VERSION 5.7 ;
  NOWIREEXTENSIONATPIN ON ;
  DIVIDERCHAR "/" ;
  BUSBITCHARS "[]" ;
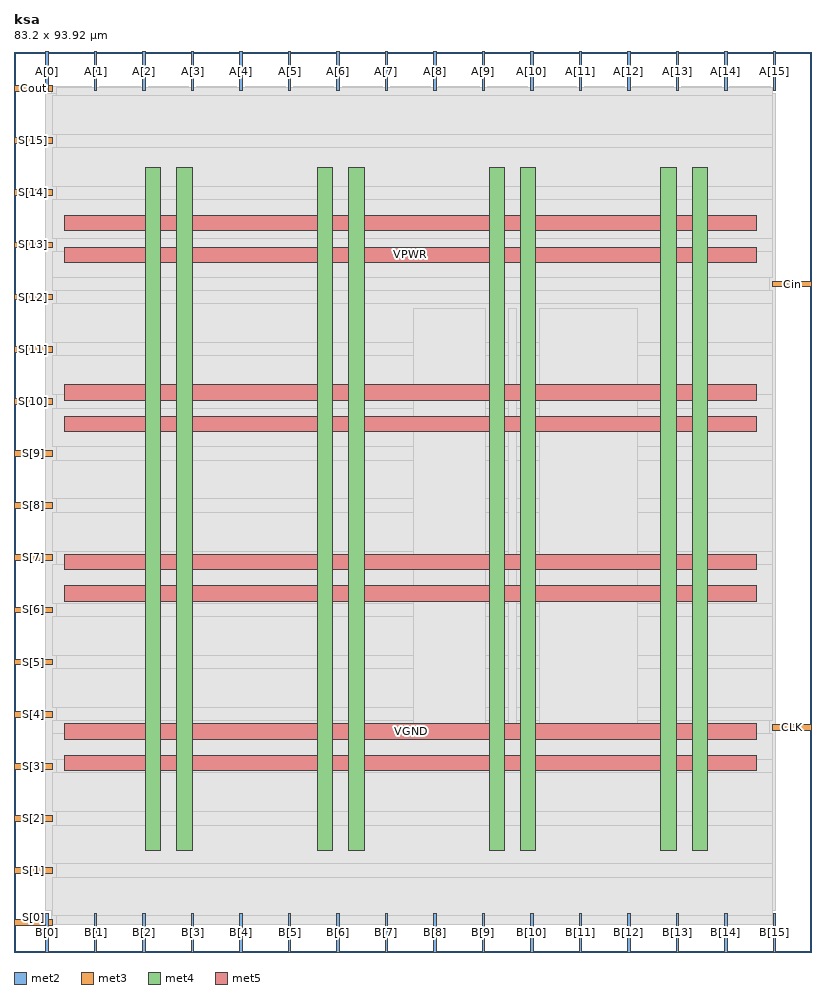
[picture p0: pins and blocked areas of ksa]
MACRO ksa
  CLASS BLOCK ;
  FOREIGN ksa ;
  ORIGIN 0.000 0.000 ;
  SIZE 83.200 BY 93.920 ;
  PIN A[0]
    DIRECTION INPUT ;
    USE SIGNAL ;
    ANTENNAGATEAREA 0.196500 ;
    PORT
      LAYER met2 ;
        RECT 3.310 89.920 3.590 93.920 ;
    END
  END A[0]
  PIN A[10]
    DIRECTION INPUT ;
    USE SIGNAL ;
    ANTENNAGATEAREA 0.196500 ;
    PORT
      LAYER met2 ;
        RECT 53.910 89.920 54.190 93.920 ;
    END
  END A[10]
  PIN A[11]
    DIRECTION INPUT ;
    USE SIGNAL ;
    ANTENNAGATEAREA 0.196500 ;
    PORT
      LAYER met2 ;
        RECT 58.970 89.920 59.250 93.920 ;
    END
  END A[11]
  PIN A[12]
    DIRECTION INPUT ;
    USE SIGNAL ;
    ANTENNAGATEAREA 0.196500 ;
    PORT
      LAYER met2 ;
        RECT 64.030 89.920 64.310 93.920 ;
    END
  END A[12]
  PIN A[13]
    DIRECTION INPUT ;
    USE SIGNAL ;
    ANTENNAGATEAREA 0.196500 ;
    PORT
      LAYER met2 ;
        RECT 69.090 89.920 69.370 93.920 ;
    END
  END A[13]
  PIN A[14]
    DIRECTION INPUT ;
    USE SIGNAL ;
    ANTENNAGATEAREA 0.196500 ;
    PORT
      LAYER met2 ;
        RECT 74.150 89.920 74.430 93.920 ;
    END
  END A[14]
  PIN A[15]
    DIRECTION INPUT ;
    USE SIGNAL ;
    ANTENNAGATEAREA 0.196500 ;
    PORT
      LAYER met2 ;
        RECT 79.210 89.920 79.490 93.920 ;
    END
  END A[15]
  PIN A[1]
    DIRECTION INPUT ;
    USE SIGNAL ;
    ANTENNAGATEAREA 0.196500 ;
    PORT
      LAYER met2 ;
        RECT 8.370 89.920 8.650 93.920 ;
    END
  END A[1]
  PIN A[2]
    DIRECTION INPUT ;
    USE SIGNAL ;
    ANTENNAGATEAREA 0.196500 ;
    PORT
      LAYER met2 ;
        RECT 13.430 89.920 13.710 93.920 ;
    END
  END A[2]
  PIN A[3]
    DIRECTION INPUT ;
    USE SIGNAL ;
    ANTENNAGATEAREA 0.196500 ;
    PORT
      LAYER met2 ;
        RECT 18.490 89.920 18.770 93.920 ;
    END
  END A[3]
  PIN A[4]
    DIRECTION INPUT ;
    USE SIGNAL ;
    ANTENNAGATEAREA 0.196500 ;
    PORT
      LAYER met2 ;
        RECT 23.550 89.920 23.830 93.920 ;
    END
  END A[4]
  PIN A[5]
    DIRECTION INPUT ;
    USE SIGNAL ;
    ANTENNAGATEAREA 0.196500 ;
    PORT
      LAYER met2 ;
        RECT 28.610 89.920 28.890 93.920 ;
    END
  END A[5]
  PIN A[6]
    DIRECTION INPUT ;
    USE SIGNAL ;
    ANTENNAGATEAREA 0.196500 ;
    PORT
      LAYER met2 ;
        RECT 33.670 89.920 33.950 93.920 ;
    END
  END A[6]
  PIN A[7]
    DIRECTION INPUT ;
    USE SIGNAL ;
    ANTENNAGATEAREA 0.196500 ;
    PORT
      LAYER met2 ;
        RECT 38.730 89.920 39.010 93.920 ;
    END
  END A[7]
  PIN A[8]
    DIRECTION INPUT ;
    USE SIGNAL ;
    ANTENNAGATEAREA 0.196500 ;
    PORT
      LAYER met2 ;
        RECT 43.790 89.920 44.070 93.920 ;
    END
  END A[8]
  PIN A[9]
    DIRECTION INPUT ;
    USE SIGNAL ;
    ANTENNAGATEAREA 0.196500 ;
    PORT
      LAYER met2 ;
        RECT 48.850 89.920 49.130 93.920 ;
    END
  END A[9]
  PIN B[0]
    DIRECTION INPUT ;
    USE SIGNAL ;
    ANTENNAGATEAREA 0.196500 ;
    PORT
      LAYER met2 ;
        RECT 3.310 0.000 3.590 4.000 ;
    END
  END B[0]
  PIN B[10]
    DIRECTION INPUT ;
    USE SIGNAL ;
    ANTENNAGATEAREA 0.196500 ;
    PORT
      LAYER met2 ;
        RECT 53.910 0.000 54.190 4.000 ;
    END
  END B[10]
  PIN B[11]
    DIRECTION INPUT ;
    USE SIGNAL ;
    ANTENNAGATEAREA 0.196500 ;
    PORT
      LAYER met2 ;
        RECT 58.970 0.000 59.250 4.000 ;
    END
  END B[11]
  PIN B[12]
    DIRECTION INPUT ;
    USE SIGNAL ;
    ANTENNAGATEAREA 0.196500 ;
    PORT
      LAYER met2 ;
        RECT 64.030 0.000 64.310 4.000 ;
    END
  END B[12]
  PIN B[13]
    DIRECTION INPUT ;
    USE SIGNAL ;
    ANTENNAGATEAREA 0.196500 ;
    PORT
      LAYER met2 ;
        RECT 69.090 0.000 69.370 4.000 ;
    END
  END B[13]
  PIN B[14]
    DIRECTION INPUT ;
    USE SIGNAL ;
    ANTENNAGATEAREA 0.196500 ;
    PORT
      LAYER met2 ;
        RECT 74.150 0.000 74.430 4.000 ;
    END
  END B[14]
  PIN B[15]
    DIRECTION INPUT ;
    USE SIGNAL ;
    ANTENNAGATEAREA 0.196500 ;
    PORT
      LAYER met2 ;
        RECT 79.210 0.000 79.490 4.000 ;
    END
  END B[15]
  PIN B[1]
    DIRECTION INPUT ;
    USE SIGNAL ;
    ANTENNAGATEAREA 0.196500 ;
    PORT
      LAYER met2 ;
        RECT 8.370 0.000 8.650 4.000 ;
    END
  END B[1]
  PIN B[2]
    DIRECTION INPUT ;
    USE SIGNAL ;
    ANTENNAGATEAREA 0.196500 ;
    PORT
      LAYER met2 ;
        RECT 13.430 0.000 13.710 4.000 ;
    END
  END B[2]
  PIN B[3]
    DIRECTION INPUT ;
    USE SIGNAL ;
    ANTENNAGATEAREA 0.196500 ;
    PORT
      LAYER met2 ;
        RECT 18.490 0.000 18.770 4.000 ;
    END
  END B[3]
  PIN B[4]
    DIRECTION INPUT ;
    USE SIGNAL ;
    ANTENNAGATEAREA 0.196500 ;
    PORT
      LAYER met2 ;
        RECT 23.550 0.000 23.830 4.000 ;
    END
  END B[4]
  PIN B[5]
    DIRECTION INPUT ;
    USE SIGNAL ;
    ANTENNAGATEAREA 0.196500 ;
    PORT
      LAYER met2 ;
        RECT 28.610 0.000 28.890 4.000 ;
    END
  END B[5]
  PIN B[6]
    DIRECTION INPUT ;
    USE SIGNAL ;
    ANTENNAGATEAREA 0.196500 ;
    PORT
      LAYER met2 ;
        RECT 33.670 0.000 33.950 4.000 ;
    END
  END B[6]
  PIN B[7]
    DIRECTION INPUT ;
    USE SIGNAL ;
    ANTENNAGATEAREA 0.196500 ;
    PORT
      LAYER met2 ;
        RECT 38.730 0.000 39.010 4.000 ;
    END
  END B[7]
  PIN B[8]
    DIRECTION INPUT ;
    USE SIGNAL ;
    ANTENNAGATEAREA 0.196500 ;
    PORT
      LAYER met2 ;
        RECT 43.790 0.000 44.070 4.000 ;
    END
  END B[8]
  PIN B[9]
    DIRECTION INPUT ;
    USE SIGNAL ;
    ANTENNAGATEAREA 0.196500 ;
    PORT
      LAYER met2 ;
        RECT 48.850 0.000 49.130 4.000 ;
    END
  END B[9]
  PIN CLK
    DIRECTION INPUT ;
    USE SIGNAL ;
    ANTENNAGATEAREA 0.852000 ;
    PORT
      LAYER met3 ;
        RECT 79.200 23.160 83.200 23.760 ;
    END
  END CLK
  PIN Cin
    DIRECTION INPUT ;
    USE SIGNAL ;
    ANTENNAGATEAREA 0.196500 ;
    PORT
      LAYER met3 ;
        RECT 79.200 69.400 83.200 70.000 ;
    END
  END Cin
  PIN Cout
    DIRECTION OUTPUT ;
    USE SIGNAL ;
    ANTENNADIFFAREA 0.340600 ;
    PORT
      LAYER met3 ;
        RECT 0.000 89.800 4.000 90.400 ;
    END
  END Cout
  PIN S[0]
    DIRECTION OUTPUT ;
    USE SIGNAL ;
    ANTENNADIFFAREA 0.340600 ;
    PORT
      LAYER met3 ;
        RECT 0.000 2.760 4.000 3.360 ;
    END
  END S[0]
  PIN S[10]
    DIRECTION OUTPUT ;
    USE SIGNAL ;
    ANTENNADIFFAREA 0.340600 ;
    PORT
      LAYER met3 ;
        RECT 0.000 57.160 4.000 57.760 ;
    END
  END S[10]
  PIN S[11]
    DIRECTION OUTPUT ;
    USE SIGNAL ;
    ANTENNADIFFAREA 0.340600 ;
    PORT
      LAYER met3 ;
        RECT 0.000 62.600 4.000 63.200 ;
    END
  END S[11]
  PIN S[12]
    DIRECTION OUTPUT ;
    USE SIGNAL ;
    ANTENNADIFFAREA 0.340600 ;
    PORT
      LAYER met3 ;
        RECT 0.000 68.040 4.000 68.640 ;
    END
  END S[12]
  PIN S[13]
    DIRECTION OUTPUT ;
    USE SIGNAL ;
    ANTENNADIFFAREA 0.340600 ;
    PORT
      LAYER met3 ;
        RECT 0.000 73.480 4.000 74.080 ;
    END
  END S[13]
  PIN S[14]
    DIRECTION OUTPUT ;
    USE SIGNAL ;
    ANTENNADIFFAREA 0.340600 ;
    PORT
      LAYER met3 ;
        RECT 0.000 78.920 4.000 79.520 ;
    END
  END S[14]
  PIN S[15]
    DIRECTION OUTPUT ;
    USE SIGNAL ;
    ANTENNADIFFAREA 0.340600 ;
    PORT
      LAYER met3 ;
        RECT 0.000 84.360 4.000 84.960 ;
    END
  END S[15]
  PIN S[1]
    DIRECTION OUTPUT ;
    USE SIGNAL ;
    ANTENNADIFFAREA 0.340600 ;
    PORT
      LAYER met3 ;
        RECT 0.000 8.200 4.000 8.800 ;
    END
  END S[1]
  PIN S[2]
    DIRECTION OUTPUT ;
    USE SIGNAL ;
    ANTENNADIFFAREA 0.340600 ;
    PORT
      LAYER met3 ;
        RECT 0.000 13.640 4.000 14.240 ;
    END
  END S[2]
  PIN S[3]
    DIRECTION OUTPUT ;
    USE SIGNAL ;
    ANTENNADIFFAREA 0.340600 ;
    PORT
      LAYER met3 ;
        RECT 0.000 19.080 4.000 19.680 ;
    END
  END S[3]
  PIN S[4]
    DIRECTION OUTPUT ;
    USE SIGNAL ;
    ANTENNADIFFAREA 0.340600 ;
    PORT
      LAYER met3 ;
        RECT 0.000 24.520 4.000 25.120 ;
    END
  END S[4]
  PIN S[5]
    DIRECTION OUTPUT ;
    USE SIGNAL ;
    ANTENNADIFFAREA 0.340600 ;
    PORT
      LAYER met3 ;
        RECT 0.000 29.960 4.000 30.560 ;
    END
  END S[5]
  PIN S[6]
    DIRECTION OUTPUT ;
    USE SIGNAL ;
    ANTENNADIFFAREA 0.340600 ;
    PORT
      LAYER met3 ;
        RECT 0.000 35.400 4.000 36.000 ;
    END
  END S[6]
  PIN S[7]
    DIRECTION OUTPUT ;
    USE SIGNAL ;
    ANTENNADIFFAREA 0.340600 ;
    PORT
      LAYER met3 ;
        RECT 0.000 40.840 4.000 41.440 ;
    END
  END S[7]
  PIN S[8]
    DIRECTION OUTPUT ;
    USE SIGNAL ;
    ANTENNADIFFAREA 0.340600 ;
    PORT
      LAYER met3 ;
        RECT 0.000 46.280 4.000 46.880 ;
    END
  END S[8]
  PIN S[9]
    DIRECTION OUTPUT ;
    USE SIGNAL ;
    ANTENNADIFFAREA 0.340600 ;
    PORT
      LAYER met3 ;
        RECT 0.000 51.720 4.000 52.320 ;
    END
  END S[9]
  PIN VGND
    DIRECTION INOUT ;
    USE GROUND ;
    PORT
      LAYER met4 ;
        RECT 16.990 10.640 18.590 81.840 ;
    END
    PORT
      LAYER met4 ;
        RECT 34.930 10.640 36.530 81.840 ;
    END
    PORT
      LAYER met4 ;
        RECT 52.870 10.640 54.470 81.840 ;
    END
    PORT
      LAYER met4 ;
        RECT 70.810 10.640 72.410 81.840 ;
    END
    PORT
      LAYER met5 ;
        RECT 5.280 22.220 77.520 23.820 ;
    END
    PORT
      LAYER met5 ;
        RECT 5.280 39.900 77.520 41.500 ;
    END
    PORT
      LAYER met5 ;
        RECT 5.280 57.580 77.520 59.180 ;
    END
    PORT
      LAYER met5 ;
        RECT 5.280 75.260 77.520 76.860 ;
    END
  END VGND
  PIN VPWR
    DIRECTION INOUT ;
    USE POWER ;
    PORT
      LAYER met4 ;
        RECT 13.690 10.640 15.290 81.840 ;
    END
    PORT
      LAYER met4 ;
        RECT 31.630 10.640 33.230 81.840 ;
    END
    PORT
      LAYER met4 ;
        RECT 49.570 10.640 51.170 81.840 ;
    END
    PORT
      LAYER met4 ;
        RECT 67.510 10.640 69.110 81.840 ;
    END
    PORT
      LAYER met5 ;
        RECT 5.280 18.920 77.520 20.520 ;
    END
    PORT
      LAYER met5 ;
        RECT 5.280 36.600 77.520 38.200 ;
    END
    PORT
      LAYER met5 ;
        RECT 5.280 54.280 77.520 55.880 ;
    END
    PORT
      LAYER met5 ;
        RECT 5.280 71.960 77.520 73.560 ;
    END
  END VPWR
  OBS
      LAYER nwell ;
        RECT 5.330 10.795 77.470 81.685 ;
      LAYER li1 ;
        RECT 5.520 10.795 77.280 81.685 ;
      LAYER met1 ;
        RECT 3.290 10.640 79.510 81.840 ;
      LAYER met2 ;
        RECT 3.870 89.640 8.090 90.285 ;
        RECT 8.930 89.640 13.150 90.285 ;
        RECT 13.990 89.640 18.210 90.285 ;
        RECT 19.050 89.640 23.270 90.285 ;
        RECT 24.110 89.640 28.330 90.285 ;
        RECT 29.170 89.640 33.390 90.285 ;
        RECT 34.230 89.640 38.450 90.285 ;
        RECT 39.290 89.640 43.510 90.285 ;
        RECT 44.350 89.640 48.570 90.285 ;
        RECT 49.410 89.640 53.630 90.285 ;
        RECT 54.470 89.640 58.690 90.285 ;
        RECT 59.530 89.640 63.750 90.285 ;
        RECT 64.590 89.640 68.810 90.285 ;
        RECT 69.650 89.640 73.870 90.285 ;
        RECT 74.710 89.640 78.930 90.285 ;
        RECT 3.320 4.280 79.480 89.640 ;
        RECT 3.870 2.875 8.090 4.280 ;
        RECT 8.930 2.875 13.150 4.280 ;
        RECT 13.990 2.875 18.210 4.280 ;
        RECT 19.050 2.875 23.270 4.280 ;
        RECT 24.110 2.875 28.330 4.280 ;
        RECT 29.170 2.875 33.390 4.280 ;
        RECT 34.230 2.875 38.450 4.280 ;
        RECT 39.290 2.875 43.510 4.280 ;
        RECT 44.350 2.875 48.570 4.280 ;
        RECT 49.410 2.875 53.630 4.280 ;
        RECT 54.470 2.875 58.690 4.280 ;
        RECT 59.530 2.875 63.750 4.280 ;
        RECT 64.590 2.875 68.810 4.280 ;
        RECT 69.650 2.875 73.870 4.280 ;
        RECT 74.710 2.875 78.930 4.280 ;
      LAYER met3 ;
        RECT 4.400 89.400 79.200 90.265 ;
        RECT 3.990 85.360 79.200 89.400 ;
        RECT 4.400 83.960 79.200 85.360 ;
        RECT 3.990 79.920 79.200 83.960 ;
        RECT 4.400 78.520 79.200 79.920 ;
        RECT 3.990 74.480 79.200 78.520 ;
        RECT 4.400 73.080 79.200 74.480 ;
        RECT 3.990 70.400 79.200 73.080 ;
        RECT 3.990 69.040 78.800 70.400 ;
        RECT 4.400 69.000 78.800 69.040 ;
        RECT 4.400 67.640 79.200 69.000 ;
        RECT 3.990 63.600 79.200 67.640 ;
        RECT 4.400 62.200 79.200 63.600 ;
        RECT 3.990 58.160 79.200 62.200 ;
        RECT 4.400 56.760 79.200 58.160 ;
        RECT 3.990 52.720 79.200 56.760 ;
        RECT 4.400 51.320 79.200 52.720 ;
        RECT 3.990 47.280 79.200 51.320 ;
        RECT 4.400 45.880 79.200 47.280 ;
        RECT 3.990 41.840 79.200 45.880 ;
        RECT 4.400 40.440 79.200 41.840 ;
        RECT 3.990 36.400 79.200 40.440 ;
        RECT 4.400 35.000 79.200 36.400 ;
        RECT 3.990 30.960 79.200 35.000 ;
        RECT 4.400 29.560 79.200 30.960 ;
        RECT 3.990 25.520 79.200 29.560 ;
        RECT 4.400 24.160 79.200 25.520 ;
        RECT 4.400 24.120 78.800 24.160 ;
        RECT 3.990 22.760 78.800 24.120 ;
        RECT 3.990 20.080 79.200 22.760 ;
        RECT 4.400 18.680 79.200 20.080 ;
        RECT 3.990 14.640 79.200 18.680 ;
        RECT 4.400 13.240 79.200 14.640 ;
        RECT 3.990 9.200 79.200 13.240 ;
        RECT 4.400 7.800 79.200 9.200 ;
        RECT 3.990 3.760 79.200 7.800 ;
        RECT 4.400 2.895 79.200 3.760 ;
      LAYER met4 ;
        RECT 41.695 23.295 49.170 67.145 ;
        RECT 51.570 23.295 52.470 67.145 ;
        RECT 54.870 23.295 65.025 67.145 ;
  END
END ksa
END LIBRARY

